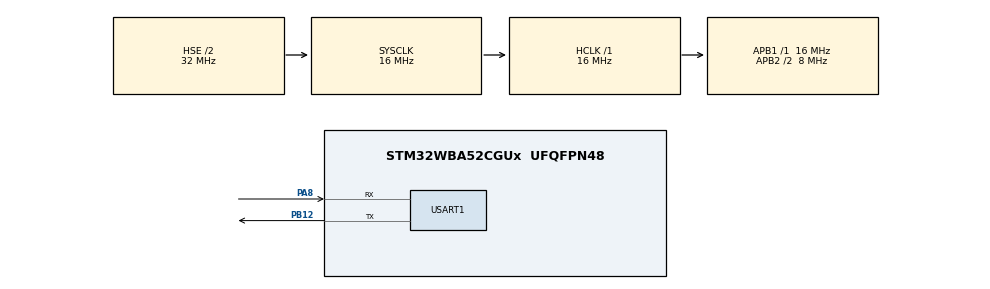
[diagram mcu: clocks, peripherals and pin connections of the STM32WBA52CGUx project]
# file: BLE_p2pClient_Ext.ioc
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ADC4.Channel-0\#ChannelRegularConversion=ADC_CHANNEL_TEMPSENSOR
ADC4.NbrOfConversionFlag=1
ADC4.Overrun=ADC_OVR_DATA_OVERWRITTEN
ADC4.Rank-0\#ChannelRegularConversion=1
ADC4.SamplingTime-0\#ChannelRegularConversion=ADC_SAMPLINGTIME_COMMON_1
ADC4.SamplingTimeCommon1=ADC_SAMPLETIME_814CYCLES_5
ADC4.SelectedChannel=ADC_CHANNEL_TEMPSENSOR
CORTEX_M33_NS.userName=CORTEX_M33
GPDMA1.DESTINC_GPDMACH1=DMA_DINC_INCREMENTED
GPDMA1.DIRECTION_GPDMACH0=DMA_MEMORY_TO_PERIPH
GPDMA1.IPHANDLE_GPDMACH0-SIMPLEREQUEST_GPDMACH0=__NULL
GPDMA1.IPHANDLE_GPDMACH1-SIMPLEREQUEST_GPDMACH1=__NULL
GPDMA1.REQUEST_GPDMACH0=GPDMA1_REQUEST_USART1_TX
GPDMA1.REQUEST_GPDMACH1=GPDMA1_REQUEST_USART1_RX
GPDMA1.SRCINC_GPDMACH0=DMA_SINC_INCREMENTED
Mcu.Family=STM32WBA
Mcu.Name=STM32WBA52CGUx
Mcu.Package=UFQFPN48
NVIC.GPDMA1_Channel0_IRQn=true\:6\:0\:true\:false\:true\:true\:true\:true
NVIC.GPDMA1_Channel1_IRQn=true\:5\:0\:true\:false\:true\:true\:true\:true
NVIC.PriorityGroup=NVIC_PRIORITYGROUP_4
NVIC.RADIO_IRQn=true\:0\:0\:true\:false\:true\:true\:false\:true
NVIC.RCC_IRQn=true\:1\:0\:true\:false\:true\:true\:false\:true
NVIC.RNG_IRQn=true\:0\:0\:false\:false\:true\:true\:true\:true
NVIC.RTC_IRQn=true\:4\:0\:true\:false\:true\:true\:true\:true
NVIC.USART1_IRQn=true\:7\:0\:true\:false\:true\:true\:true\:true
OSC_IN.Mode=HSE-External-Oscillator
OSC_IN.Signal=RCC_OSC_IN
OSC_OUT.Mode=HSE-External-Oscillator
OSC_OUT.Signal=RCC_OSC_OUT
PA13\ (JTMS/SWDIO).Mode=Serial_Wire
PA13\ (JTMS/SWDIO).Signal=DEBUG_JTMS-SWDIO
PA14\ (JTCK/SWCLK).Mode=Serial_Wire
PA14\ (JTCK/SWCLK).Signal=DEBUG_JTCK-SWCLK
PA8.Mode=Asynchronous
PA8.Signal=USART1_RX
PB12.Mode=Asynchronous
PB12.Signal=USART1_TX
PC14-OSC32_IN.Mode=LSE-External-Oscillator
PC14-OSC32_IN.Signal=RCC_OSC32_IN
PC15-OSC32_OUT.Mode=LSE-External-Oscillator
PC15-OSC32_OUT.Signal=RCC_OSC32_OUT
PWR.pwrPrivilege=PWR_PRIVILEGE_NO
ProjectManager.HeapSize=0x3000
ProjectManager.StackSize=0x1000
ProjectManager.TargetToolchain=EWARM V9.20
RAMCFG.Instance-RAMCFG1_Activate=RAMCFG_SRAM1
RCC.ADCFreq_Value=16000000
RCC.AHBFreq_Value=16000000
RCC.APB1Freq_Value=16000000
RCC.APB1TimFreq_Value=16000000
RCC.APB2CLKDivider=RCC_HCLK_DIV2
RCC.APB2Freq_Value=8000000
RCC.APB2TimFreq_Value=16000000
RCC.CortexFreq_Value=2000000
RCC.HCLKFreq_Value=16000000
RCC.HSE_VALUE=32000000
RCC.HSI_VALUE=16000000
RCC.HseDiv=RCC_HSE_DIV2
RCC.PLLFRACN=0
RCC.PLLN=8
RCC.PREFETCH_ENABLE=1
RCC.PWR_Regulator_Voltage_Scale=PWR_REGULATOR_VOLTAGE_SCALE2
RCC.RCC_MCODiv=RCC_MCODIV_16
RCC.RSTClockSelectionVirtual=RCC_RADIOSTCLKSOURCE_LSE
RCC.RTCClockSelection=RCC_RTCCLKSOURCE_LSE
RCC.SYSCLKFreq_VALUE=16000000
RCC.SYSCLKSourceVirtual=RCC_SYSCLKSOURCE_HSE
RCC.USART1CLockSelectionVirtual=RCC_USART1CLKSOURCE_HSI
RCC.VCOOutputFreq_Value=128000000
RNG.ClockErrorDetection=RNG_CED_DISABLE
RTC.Alarm-Alarm\ A=RTC_ALARM_A
RTC.AsynchPrediv=31
RTC.BinMode=RTC_BINARY_ONLY
RTC.BinaryAutoClr_A-Alarm\ A=RTC_ALARMSUBSECONDBIN_AUTOCLR_NO
STM32_WPAN.BLE_OPTIONS_APPEARANCE_WRITABLE=0
STM32_WPAN.BLE_OPTIONS_DEV_NAME_READ_ONLY=0
STM32_WPAN.BLE_OPTIONS_ENHANCED_ATT=0
STM32_WPAN.BLE_OPTIONS_EXTENDED_ADV=BLE_OPTIONS_EXTENDED_ADV
STM32_WPAN.BLE_OPTIONS_GATT_CACHING=0
STM32_WPAN.BLE_OPTIONS_LL_ONLY=0
STM32_WPAN.BLE_OPTIONS_NO_SVC_CHANGE_DESC=0
STM32_WPAN.BLE_OPTIONS_POWER_CLASS_1=0
STM32_WPAN.BLE_OPTIONS_REDUCED_DB_IN_NVM=0
STM32_WPAN.BSP.number=1
STM32_WPAN.CFG_AMM_VIRTUAL_BUFFER_SIZE_1=400
STM32_WPAN.CFG_BD_ADDRESS_TYPE=GAP_PUBLIC_ADDR
STM32_WPAN.CFG_BLE_ATT_MTU_MAX=251
STM32_WPAN.CFG_BLE_EXTENDED_ADV=1
STM32_WPAN.CFG_BLE_NUM_LINK=8
STM32_WPAN.CFG_BONDING_MODE=1
STM32_WPAN.CFG_DEBUG_APP_TRACE=1
STM32_WPAN.CFG_DEBUG_TRACE_FULL=1
STM32_WPAN.CFG_HW_USART1_ENABLED=1
STM32_WPAN.CFG_MM_POOL_SIZE=4000
STM32_WPAN.CFG_TX_POWER=(0x19) /* 0x19 <\=> -0.3 dBm */
STM32_WPAN.NEXT_EVENT_SCHEDULING_FROM_ISR=1
STM32_WPAN.RADIO_INTR_PRIO_LOW=5
STM32_WPAN.RADIO_SW_LOW_INTR_NUM=HASH_IRQn
STM32_WPAN.RT_DEBUG_GPIO_MODULE=0
STM32_WPAN.SNVMA_POLY_CRC16=1DB7
STM32_WPAN.STATIC_RANDOM_ADDRESS=0x123412341234
STM32_WPAN0.BSP.STBoard=false
STM32_WPAN0.BSP.api=Unknown
STM32_WPAN0.BSP.condition=((USART1 | USART2 | S_LPUART) & (Semaphore_ADV_TRACE_TIMESTAMP_ENABLE | CFG_DEBUG_APP_TRACE | CFG_DEBUG_TRACE_LIGHT | CFG_DEBUG_TRACE_FULL))
STM32_WPAN0.BSP.instance=USART1
STM32_WPAN0.BSP.ip=(LPU|US)ART
STM32_WPAN0.BSP.mode=Asynchronous
STM32_WPAN0.BSP.name=Serial Link for Traces
STM32_WPAN0.BSP.solution=USART1
USART1.FIFOMode=FIFOMODE_ENABLE
USART1.OverSampling=UART_OVERSAMPLING_8
USART1.VirtualMode-Asynchronous=VM_ASYNC
VP_ADC4_TempSens_Input.Mode=IN-TempSens
VP_ADV_TRACE_VS_ADV_TRACE.Mode=ADV_TRACE_Enabled
VP_CRC_VS_CRC.Mode=CRC_Activate
VP_GPDMA1_VS_GPDMACH0.Mode=SIMPLEREQUEST_GPDMACH0
VP_GPDMA1_VS_GPDMACH1.Mode=SIMPLEREQUEST_GPDMACH1
VP_ICACHE_VS_ICACHE.Mode=DirectMappedCache
VP_MISC_VS_MISC.Mode=MISC_Enabled
VP_PWR_VS_SECSignals.Mode=Security/Privilege
VP_RAMCFG_VS_RAMCFG1.Mode=RAMCFG1_Activate
VP_RF_VS_RF.Mode=RF_Activate
VP_RNG_VS_RNG.Mode=RNG_Activate
VP_RTC_VS_RTC_Activate.Mode=RTC_Enabled
VP_RTC_VS_RTC_Alarm_A_Intern.Mode=Alarm A
VP_RTC_VS_RTC_Calendar.Mode=RTC_Calendar
VP_SEQUENCER_VS_SEQUENCER.Mode=SEQUENCER_Enabled
VP_STM32_WPAN_VS_BLE_HOST_CP.Mode=BLE_Client
VP_TIMER_VS_TIMER.Mode=TIMER_Enabled
VP_TINY_LPM_VS_TINY_LPM.Mode=TINY_LPM_Enabled
board=custom

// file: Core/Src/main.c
/* USER CODE BEGIN Header */
/**
  ******************************************************************************
  * @file           : main.c
  * @brief          : Main program body
  ******************************************************************************
  * @attention
  *
  * Copyright (c) 2022 STMicroelectronics.
  * All rights reserved.
  *
  * This software is licensed under terms that can be found in the LICENSE file
  * in the root directory of this software component.
  * If no LICENSE file comes with this software, it is provided AS-IS.
  *
  ******************************************************************************
  */
/* USER CODE END Header */
#include "main.h"

ADC_HandleTypeDef hadc4;

CRC_HandleTypeDef hcrc;

RAMCFG_HandleTypeDef hramcfg_SRAM1;

RNG_HandleTypeDef hrng;

RTC_HandleTypeDef hrtc;

UART_HandleTypeDef huart1;
DMA_HandleTypeDef handle_GPDMA1_Channel1;
DMA_HandleTypeDef handle_GPDMA1_Channel0;

void SystemClock_Config(void);
void PeriphCommonClock_Config(void);
static void MX_GPDMA1_Init(void);
static void MX_ADC4_Init(void);

int main(void)
{

  /* MCU Configuration--------------------------------------------------------*/

  /* Reset of all peripherals, Initializes the Flash interface and the Systick. */
  HAL_Init();
  /* Config code for STM32_WPAN (HSE Tuning must be done before system clock configuration) */
  MX_APPE_Config();

  /* Configure the system clock */
  SystemClock_Config();

/* Configure the peripherals common clocks */
  PeriphCommonClock_Config();

  /* Initialize all configured peripherals */
  MX_GPIO_Init();
  MX_GPDMA1_Init();
  MX_ICACHE_Init();
  MX_RAMCFG_Init();
  MX_RTC_Init();
  MX_USART1_UART_Init();
  MX_ADC4_Init();
  MX_RNG_Init();

  /* Init code for STM32_WPAN */
  MX_APPE_Init(NULL);

  /* Infinite loop */
  while (1)
  {
    MX_APPE_Process();

  }
}

void SystemClock_Config(void)
{
  RCC_OscInitTypeDef RCC_OscInitStruct = {0};
  RCC_ClkInitTypeDef RCC_ClkInitStruct = {0};

  /** Configure the main internal regulator output voltage
  */
  if (HAL_PWREx_ControlVoltageScaling(PWR_REGULATOR_VOLTAGE_SCALE2) != HAL_OK)
  {
    Error_Handler();
  }

  /** Configure LSE Drive Capability
  */
  HAL_PWR_EnableBkUpAccess();
  __HAL_RCC_LSEDRIVE_CONFIG(RCC_LSEDRIVE_MEDIUMLOW);

  /** Initializes the CPU, AHB and APB busses clocks
  */
  RCC_OscInitStruct.OscillatorType = RCC_OSCILLATORTYPE_HSI|RCC_OSCILLATORTYPE_HSE
                              |RCC_OSCILLATORTYPE_LSE;
  RCC_OscInitStruct.HSEState = RCC_HSE_ON;
  RCC_OscInitStruct.HSEDiv = RCC_HSE_DIV2;
  RCC_OscInitStruct.LSEState = RCC_LSE_ON;
  RCC_OscInitStruct.HSIState = RCC_HSI_ON;
  RCC_OscInitStruct.HSICalibrationValue = RCC_HSICALIBRATION_DEFAULT;
  RCC_OscInitStruct.PLL1.PLLState = RCC_PLL_NONE;
  if (HAL_RCC_OscConfig(&RCC_OscInitStruct) != HAL_OK)
  {
    Error_Handler();
  }

  /** Initializes the CPU, AHB and APB busses clocks
  */
  RCC_ClkInitStruct.ClockType = RCC_CLOCKTYPE_HCLK|RCC_CLOCKTYPE_SYSCLK
                              |RCC_CLOCKTYPE_PCLK1|RCC_CLOCKTYPE_PCLK2
                              |RCC_CLOCKTYPE_PCLK7|RCC_CLOCKTYPE_HCLK5;
  RCC_ClkInitStruct.SYSCLKSource = RCC_SYSCLKSOURCE_HSE;
  RCC_ClkInitStruct.AHBCLKDivider = RCC_SYSCLK_DIV1;
  RCC_ClkInitStruct.APB1CLKDivider = RCC_HCLK_DIV1;
  RCC_ClkInitStruct.APB2CLKDivider = RCC_HCLK_DIV2;
  RCC_ClkInitStruct.APB7CLKDivider = RCC_HCLK_DIV1;
  RCC_ClkInitStruct.AHB5_PLL1_CLKDivider = RCC_SYSCLK_PLL1_DIV1;
  RCC_ClkInitStruct.AHB5_HSEHSI_CLKDivider = RCC_SYSCLK_HSEHSI_DIV1;

  if (HAL_RCC_ClockConfig(&RCC_ClkInitStruct, FLASH_LATENCY_1) != HAL_OK)
  {
    Error_Handler();
  }
}

void PeriphCommonClock_Config(void)
{
  RCC_PeriphCLKInitTypeDef PeriphClkInit = {0};

  /** Initializes the peripherals clock
  */
  PeriphClkInit.PeriphClockSelection = RCC_PERIPHCLK_RADIOST;
  PeriphClkInit.RadioSlpTimClockSelection = RCC_RADIOSTCLKSOURCE_LSE;

  if (HAL_RCCEx_PeriphCLKConfig(&PeriphClkInit) != HAL_OK)
  {
    Error_Handler();
  }
}

static void MX_ADC4_Init(void)
{

  ADC_ChannelConfTypeDef sConfig = {0};

  /** Common config
  */
  hadc4.Instance = ADC4;
  hadc4.Init.ClockPrescaler = ADC_CLOCK_ASYNC_DIV1;
  hadc4.Init.Resolution = ADC_RESOLUTION_12B;
  hadc4.Init.DataAlign = ADC_DATAALIGN_RIGHT;
  hadc4.Init.ScanConvMode = ADC_SCAN_DISABLE;
  hadc4.Init.EOCSelection = ADC_EOC_SINGLE_CONV;
  hadc4.Init.LowPowerAutoPowerOff = DISABLE;
  hadc4.Init.LowPowerAutonomousDPD = ADC_LP_AUTONOMOUS_DPD_DISABLE;
  hadc4.Init.LowPowerAutoWait = DISABLE;
  hadc4.Init.ContinuousConvMode = DISABLE;
  hadc4.Init.NbrOfConversion = 1;
  hadc4.Init.ExternalTrigConv = ADC_SOFTWARE_START;
  hadc4.Init.ExternalTrigConvEdge = ADC_EXTERNALTRIGCONVEDGE_NONE;
  hadc4.Init.DMAContinuousRequests = DISABLE;
  hadc4.Init.TriggerFrequencyMode = ADC_TRIGGER_FREQ_LOW;
  hadc4.Init.Overrun = ADC_OVR_DATA_OVERWRITTEN;
  hadc4.Init.SamplingTimeCommon1 = ADC_SAMPLETIME_814CYCLES_5;
  hadc4.Init.SamplingTimeCommon2 = ADC_SAMPLETIME_1CYCLE_5;
  hadc4.Init.OversamplingMode = DISABLE;
  if (HAL_ADC_Init(&hadc4) != HAL_OK)
  {
    Error_Handler();
  }

  /** Configure Regular Channel
  */
  sConfig.Channel = ADC_CHANNEL_TEMPSENSOR;
  sConfig.Rank = ADC_REGULAR_RANK_1;
  sConfig.SamplingTime = ADC_SAMPLINGTIME_COMMON_1;
  if (HAL_ADC_ConfigChannel(&hadc4, &sConfig) != HAL_OK)
  {
    Error_Handler();
  }

}

void MX_CRC_Init(void)
{

  hcrc.Instance = CRC;
  hcrc.Init.DefaultPolynomialUse = DEFAULT_POLYNOMIAL_DISABLE;
  hcrc.Init.DefaultInitValueUse = DEFAULT_INIT_VALUE_ENABLE;
  hcrc.Init.GeneratingPolynomial = 7;
  hcrc.Init.CRCLength = CRC_POLYLENGTH_16B;
  hcrc.Init.InputDataInversionMode = CRC_INPUTDATA_INVERSION_NONE;
  hcrc.Init.OutputDataInversionMode = CRC_OUTPUTDATA_INVERSION_DISABLE;
  hcrc.InputDataFormat = CRC_INPUTDATA_FORMAT_WORDS;
  if (HAL_CRC_Init(&hcrc) != HAL_OK)
  {
    Error_Handler();
  }

}

static void MX_GPDMA1_Init(void)
{

  /* Peripheral clock enable */
  __HAL_RCC_GPDMA1_CLK_ENABLE();

  /* GPDMA1 interrupt Init */
    HAL_NVIC_SetPriority(GPDMA1_Channel0_IRQn, 6, 0);
    HAL_NVIC_EnableIRQ(GPDMA1_Channel0_IRQn);
    HAL_NVIC_SetPriority(GPDMA1_Channel1_IRQn, 5, 0);
    HAL_NVIC_EnableIRQ(GPDMA1_Channel1_IRQn);

}

void MX_ICACHE_Init(void)
{

  /* USER CODE BEGIN ICACHE_Init 1 */
  /* No retention for ICACHE in stop mode */
  LL_PWR_SetICacheRAMStopRetention(LL_PWR_ICACHERAM_STOP_NO_RETENTION);
  /* USER CODE END ICACHE_Init 1 */

  /** Enable instruction cache in 1-way (direct mapped cache)
  */
  if (HAL_ICACHE_ConfigAssociativityMode(ICACHE_1WAY) != HAL_OK)
  {
    Error_Handler();
  }
  if (HAL_ICACHE_Enable() != HAL_OK)
  {
    Error_Handler();
  }

}

void MX_RAMCFG_Init(void)
{

  /** Initialize RAMCFG SRAM1
  */
  hramcfg_SRAM1.Instance = RAMCFG_SRAM1;
  if (HAL_RAMCFG_Init(&hramcfg_SRAM1) != HAL_OK)
  {
    Error_Handler();
  }

}

void MX_RNG_Init(void)
{

  /* USER CODE BEGIN RNG_Init 0 */
  memset(&hrng, 0, sizeof(hrng));
  /* USER CODE END RNG_Init 0 */

  hrng.Instance = RNG;
  hrng.Init.ClockErrorDetection = RNG_CED_DISABLE;
  if (HAL_RNG_Init(&hrng) != HAL_OK)
  {
    Error_Handler();
  }
  /* USER CODE BEGIN RNG_Init 2 */

  /* Disable RNG peripheral and its RCC clock */
  HW_RNG_Disable( );

  /* USER CODE END RNG_Init 2 */

}

void MX_RTC_Init(void)
{

  RTC_PrivilegeStateTypeDef privilegeState = {0};
  RTC_AlarmTypeDef sAlarm = {0};

  /** Initialize RTC Only
  */
  hrtc.Instance = RTC;
  hrtc.Init.AsynchPrediv = 31;
  hrtc.Init.OutPut = RTC_OUTPUT_DISABLE;
  hrtc.Init.OutPutRemap = RTC_OUTPUT_REMAP_NONE;
  hrtc.Init.OutPutPolarity = RTC_OUTPUT_POLARITY_HIGH;
  hrtc.Init.OutPutType = RTC_OUTPUT_TYPE_OPENDRAIN;
  hrtc.Init.OutPutPullUp = RTC_OUTPUT_PULLUP_NONE;
  hrtc.Init.BinMode = RTC_BINARY_ONLY;
  if (HAL_RTC_Init(&hrtc) != HAL_OK)
  {
    Error_Handler();
  }
  privilegeState.rtcPrivilegeFull = RTC_PRIVILEGE_FULL_NO;
  privilegeState.backupRegisterPrivZone = RTC_PRIVILEGE_BKUP_ZONE_NONE;
  privilegeState.backupRegisterStartZone2 = RTC_BKP_DR0;
  privilegeState.backupRegisterStartZone3 = RTC_BKP_DR0;
  if (HAL_RTCEx_PrivilegeModeSet(&hrtc, &privilegeState) != HAL_OK)
  {
    Error_Handler();
  }

  /** Initialize RTC and set the Time and Date
  */
  if (HAL_RTCEx_SetSSRU_IT(&hrtc) != HAL_OK)
  {
    Error_Handler();
  }

  /** Enable the Alarm A
  */
  sAlarm.BinaryAutoClr = RTC_ALARMSUBSECONDBIN_AUTOCLR_NO;
  sAlarm.AlarmTime.SubSeconds = 0x0;
  sAlarm.AlarmMask = RTC_ALARMMASK_NONE;
  sAlarm.AlarmSubSecondMask = RTC_ALARMSUBSECONDBINMASK_NONE;
  sAlarm.Alarm = RTC_ALARM_A;
  if (HAL_RTC_SetAlarm_IT(&hrtc, &sAlarm, RTC_FORMAT_BCD) != HAL_OK)
  {
    Error_Handler();
  }

}

void MX_USART1_UART_Init(void)
{

  huart1.Instance = USART1;
  huart1.Init.BaudRate = 115200;
  huart1.Init.WordLength = UART_WORDLENGTH_8B;
  huart1.Init.StopBits = UART_STOPBITS_1;
  huart1.Init.Parity = UART_PARITY_NONE;
  huart1.Init.Mode = UART_MODE_TX_RX;
  huart1.Init.HwFlowCtl = UART_HWCONTROL_NONE;
  huart1.Init.OverSampling = UART_OVERSAMPLING_8;
  huart1.Init.OneBitSampling = UART_ONE_BIT_SAMPLE_DISABLE;
  huart1.Init.ClockPrescaler = UART_PRESCALER_DIV1;
  huart1.AdvancedInit.AdvFeatureInit = UART_ADVFEATURE_NO_INIT;
  if (HAL_UART_Init(&huart1) != HAL_OK)
  {
    Error_Handler();
  }
  if (HAL_UARTEx_SetTxFifoThreshold(&huart1, UART_TXFIFO_THRESHOLD_1_8) != HAL_OK)
  {
    Error_Handler();
  }
  if (HAL_UARTEx_SetRxFifoThreshold(&huart1, UART_RXFIFO_THRESHOLD_1_8) != HAL_OK)
  {
    Error_Handler();
  }
  if (HAL_UARTEx_EnableFifoMode(&huart1) != HAL_OK)
  {
    Error_Handler();
  }

}

void MX_GPIO_Init(void)
{
  GPIO_InitTypeDef GPIO_InitStruct = {0};

  /* GPIO Ports Clock Enable */
  __HAL_RCC_GPIOB_CLK_ENABLE();
  __HAL_RCC_GPIOA_CLK_ENABLE();
  __HAL_RCC_GPIOC_CLK_ENABLE();
  __HAL_RCC_GPIOH_CLK_ENABLE();

  /*Configure GPIO pins : PB11 PB10 PB9 PB8
                           PB5 PB4 PB3 PB2
                           PB1 PB0 PB15 PB14
                           PB13 */
  GPIO_InitStruct.Pin = GPIO_PIN_11|GPIO_PIN_10|GPIO_PIN_9|GPIO_PIN_8
                          |GPIO_PIN_5|GPIO_PIN_4|GPIO_PIN_3|GPIO_PIN_2
                          |GPIO_PIN_1|GPIO_PIN_0|GPIO_PIN_15|GPIO_PIN_14
                          |GPIO_PIN_13;
  GPIO_InitStruct.Mode = GPIO_MODE_ANALOG;
  GPIO_InitStruct.Pull = GPIO_NOPULL;
  HAL_GPIO_Init(GPIOB, &GPIO_InitStruct);

  /*Configure GPIO pins : PA7 PA6 PA5 PA3
                           PA2 PA1 PA0 PA15
                           PA12 PA11 PA10 PA9 */
  GPIO_InitStruct.Pin = GPIO_PIN_7|GPIO_PIN_6|GPIO_PIN_5|GPIO_PIN_3
                          |GPIO_PIN_2|GPIO_PIN_1|GPIO_PIN_0|GPIO_PIN_15
                          |GPIO_PIN_12|GPIO_PIN_11|GPIO_PIN_10|GPIO_PIN_9;
  GPIO_InitStruct.Mode = GPIO_MODE_ANALOG;
  GPIO_InitStruct.Pull = GPIO_NOPULL;
  HAL_GPIO_Init(GPIOA, &GPIO_InitStruct);

  /*Configure GPIO pin : PC13 */
  GPIO_InitStruct.Pin = GPIO_PIN_13;
  GPIO_InitStruct.Mode = GPIO_MODE_IT_RISING;
  GPIO_InitStruct.Pull = GPIO_NOPULL;
  HAL_GPIO_Init(GPIOC, &GPIO_InitStruct);

  /*Configure GPIO pins : PB7 PB6 */
  GPIO_InitStruct.Pin = GPIO_PIN_7|GPIO_PIN_6;
  GPIO_InitStruct.Mode = GPIO_MODE_IT_RISING;
  GPIO_InitStruct.Pull = GPIO_NOPULL;
  HAL_GPIO_Init(GPIOB, &GPIO_InitStruct);

  /*Configure GPIO pin : PH3 */
  GPIO_InitStruct.Pin = GPIO_PIN_3;
  GPIO_InitStruct.Mode = GPIO_MODE_ANALOG;
  GPIO_InitStruct.Pull = GPIO_NOPULL;
  HAL_GPIO_Init(GPIOH, &GPIO_InitStruct);

  /*RT DEBUG GPIO_Init */
  RT_DEBUG_GPIO_Init();

  /* EXTI interrupt init*/
  HAL_NVIC_SetPriority(EXTI6_IRQn, 9, 0);
  HAL_NVIC_EnableIRQ(EXTI6_IRQn);

  HAL_NVIC_SetPriority(EXTI7_IRQn, 9, 0);
  HAL_NVIC_EnableIRQ(EXTI7_IRQn);

  HAL_NVIC_SetPriority(EXTI13_IRQn, 9, 0);
  HAL_NVIC_EnableIRQ(EXTI13_IRQn);

/* USER CODE BEGIN MX_GPIO_Init_2 */
#if (CFG_DBG_SUPPORTED == 0)
  GPIO_InitStruct.Mode = GPIO_MODE_ANALOG;
  GPIO_InitStruct.Pull = GPIO_NOPULL;
  GPIO_InitStruct.Pin = GPIO_PIN_14|GPIO_PIN_15|GPIO_PIN_13;
  HAL_GPIO_Init(GPIOA, &GPIO_InitStruct);

  GPIO_InitStruct.Mode = GPIO_MODE_ANALOG;
  GPIO_InitStruct.Pull = GPIO_NOPULL;
  GPIO_InitStruct.Pin = GPIO_PIN_3|GPIO_PIN_4;
  HAL_GPIO_Init(GPIOB, &GPIO_InitStruct);
#endif
/* USER CODE END MX_GPIO_Init_2 */
}

void Error_Handler(void)
{
  __disable_irq();
  while (1)
  {
  }
}

#ifdef  USE_FULL_ASSERT
/**
  * @brief  Reports the name of the source file and the source line number
  *         where the assert_param error has occurred.
  * @param  file: pointer to the source file name
  * @param  line: assert_param error line source number
  * @retval None
  */
void assert_failed(uint8_t *file, uint32_t line)
{
  /* USER CODE BEGIN 6 */
  /* User can add his own implementation to report the file name and line number,
     ex: printf("Wrong parameters value: file %s on line %d\r\n", file, line) */
  Error_Handler();
  /* USER CODE END 6 */
}
#endif /* USE_FULL_ASSERT */
